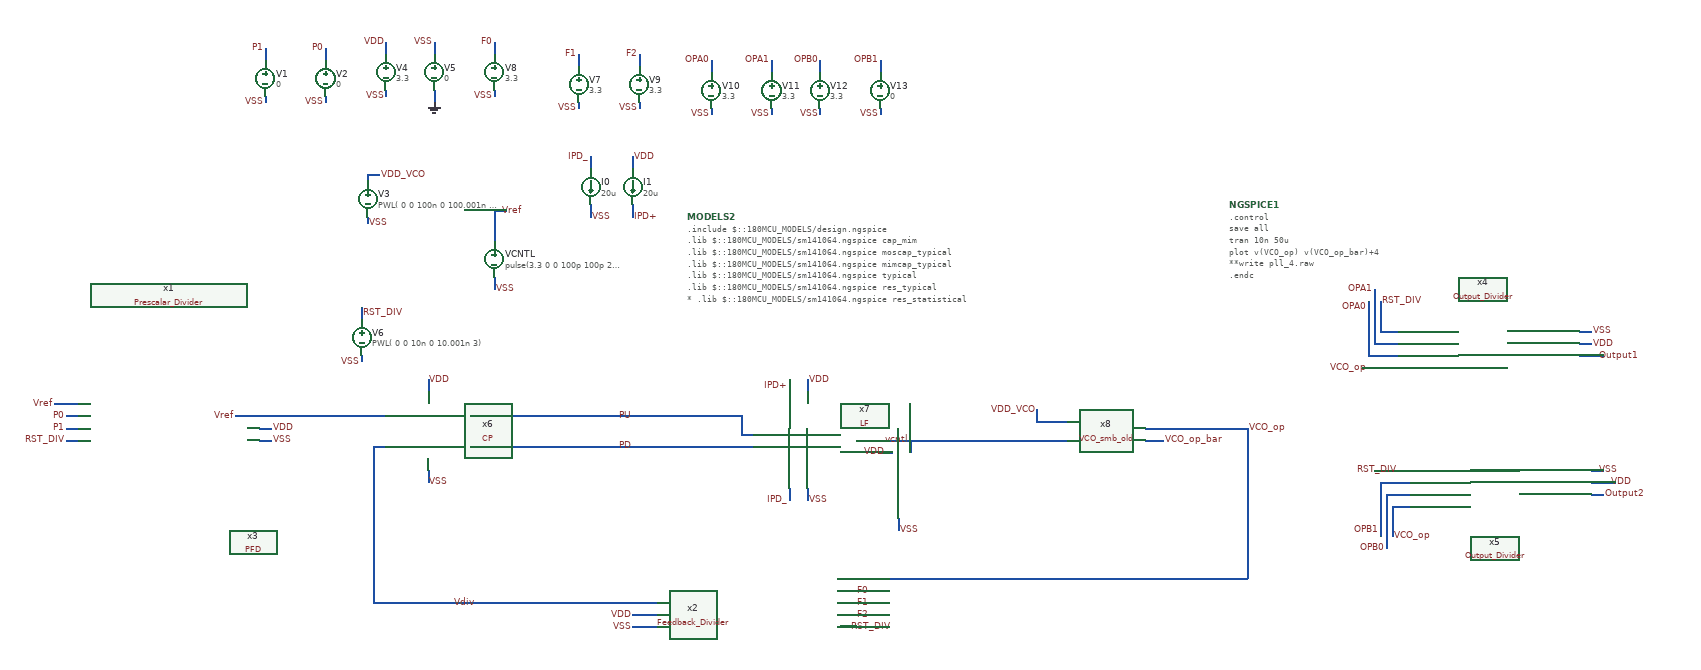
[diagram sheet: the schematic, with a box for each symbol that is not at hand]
v {xschem version=3.1.0 file_version=1.2
}
G {}
K {}
V {}
S {}
E {}
N 130 -460 150 -460 {
lab=P0}
N 130 -440 150 -440 {
lab=P1}
N 130 -420 150 -420 {
lab=RST_DIV}
N 450 -420 470 -420 {
lab=VSS}
N 450 -440 470 -440 {
lab=VDD}
N 460 -990 460 -980 {
lab=VSS}
N 460 -1070 460 -1050 {
lab=P1}
N 560 -990 560 -980 {
lab=VSS}
N 560 -1070 560 -1050 {
lab=P0}
N 730 -520 730 -500 {
lab=VDD}
N 730 -370 730 -350 {
lab=VSS}
N 640 -460 660 -460 {
lab=Vref}
N 640 -410 660 -410 {
lab=Vdiv}
N 800 -410 820 -410 {
lab=PD}
N 620 -460 640 -460 {
lab=Vref}
N 820 -460 910 -460 {
lab=PU}
N 820 -410 910 -410 {
lab=PD}
N 1100 -460 1250 -460 {
lab=PU}
N 1100 -410 1250 -410 {
lab=PD}
N 640 -410 640 -280 {
lab=Vdiv}
N 640 -180 640 -150 {
lab=Vdiv}
N 650 -150 940 -150 {
lab=Vdiv}
N 2030 -440 2090 -440 {
lab=VCO_op}
N 1970 -440 2030 -440 {
lab=VCO_op}
N 1920 -440 1970 -440 {
lab=VCO_op}
N 1740 -450 1780 -450 {
lab=VDD_VCO}
N 1920 -420 1950 -420 {
lab=VCO_op_bar}
N 640 -280 640 -180 {
lab=Vdiv}
N 640 -150 650 -150 {
lab=Vdiv}
N 800 -460 820 -460 {
lab=PU}
N 910 -460 1100 -460 {
lab=PU}
N 910 -410 1100 -410 {
lab=PD}
N 840 -690 840 -670 {
lab=VSS}
N 630 -790 630 -780 {
lab=VSS}
N 840 -800 860 -800 {
lab=Vref}
N 660 -1000 660 -990 {
lab=VSS}
N 660 -1080 660 -1060 {
lab=VDD}
N 740 -1080 740 -1060 {
lab=VSS}
N 740 -1000 740 -980 {
lab=GND}
N 1740 -470 1740 -450 {
lab=VDD_VCO}
N 940 -150 1110 -150 {
lab=Vdiv}
N 1070 -130 1110 -130 {
lab=VDD}
N 1070 -110 1110 -110 {
lab=VSS}
N 1410 -130 1440 -130 {
lab=F2}
N 1410 -110 1440 -110 {
lab=RST_DIV}
N 1440 -190 2090 -190 {
lab=VCO_op}
N 620 -560 620 -550 {
lab=VSS}
N 620 -640 620 -620 {
lab=RST_DIV}
N 2090 -440 2090 -420 {
lab=VCO_op}
N 1600 -420 1610 -420 {
lab=vcntl}
N 840 -800 840 -750 {
lab=Vref}
N 1780 -450 1790 -450 {
lab=VDD_VCO}
N 1610 -420 1770 -420 {
lab=vcntl}
N 1410 -190 1430 -190 {
lab=VCO_op}
N 1430 -190 1440 -190 {
lab=VCO_op}
N 2090 -420 2090 -190 {
lab=VCO_op}
N 1410 -170 1440 -170 {
lab=F0}
N 1410 -150 1440 -150 {
lab=F1}
N 630 -860 630 -850 {
lab=VDD_VCO}
N 630 -860 650 -860 {
lab=VDD_VCO}
N 980 -980 980 -970 {
lab=VSS}
N 980 -1060 980 -1040 {
lab=F1}
N 840 -1000 840 -990 {
lab=VSS}
N 840 -1080 840 -1060 {
lab=F0}
N 1080 -980 1080 -970 {
lab=VSS}
N 1080 -1060 1080 -1040 {
lab=F2}
N 2310 -600 2340 -600 {
lab=RST_DIV}
N 2310 -650 2310 -600 {
lab=RST_DIV}
N 2280 -540 2340 -540 {
lab=VCO_op}
N 2300 -580 2340 -580 {
lab=OPA1}
N 2300 -650 2300 -580 {
lab=OPA1}
N 2290 -560 2340 -560 {
lab=OPA0}
N 2290 -650 2290 -560 {
lab=OPA0}
N 2640 -600 2660 -600 {
lab=VSS}
N 2640 -580 2660 -580 {
lab=VDD}
N 2640 -560 2680 -560 {
lab=Output1}
N 2300 -670 2300 -650 {
lab=OPA1}
N 2330 -310 2360 -310 {
lab=VCO_op}
N 2330 -310 2330 -260 {
lab=VCO_op}
N 2300 -370 2360 -370 {
lab=RST_DIV}
N 2320 -330 2360 -330 {
lab=OPB0}
N 2320 -330 2320 -260 {
lab=OPB0}
N 2310 -350 2360 -350 {
lab=OPB1}
N 2310 -350 2310 -260 {
lab=OPB1}
N 2660 -370 2680 -370 {
lab=VSS}
N 2660 -330 2680 -330 {
lab=Output2}
N 2660 -350 2700 -350 {
lab=VDD}
N 2320 -260 2320 -240 {
lab=OPB0}
N 1200 -970 1200 -960 {
lab=VSS}
N 1200 -1050 1200 -1030 {
lab=OPA0}
N 1300 -970 1300 -960 {
lab=VSS}
N 1300 -1050 1300 -1030 {
lab=OPA1}
N 1380 -970 1380 -960 {
lab=VSS}
N 1380 -1050 1380 -1030 {
lab=OPB0}
N 1480 -970 1480 -960 {
lab=VSS}
N 1480 -1050 1480 -1030 {
lab=OPB1}
N 1360 -520 1360 -500 {
lab=VDD}
N 1360 -340 1360 -320 {
lab=VSS}
N 1250 -460 1250 -440 {
lab=PU}
N 1250 -440 1250 -430 {
lab=PU}
N 1250 -430 1270 -430 {
lab=PU}
N 1250 -410 1270 -410 {
lab=PD}
N 1510 -290 1510 -270 {
lab=VSS}
N 1330 -520 1330 -500 {
lab=IPD+}
N 1330 -340 1330 -320 {
lab=IPD_}
N 1440 -420 1600 -420 {
lab=vcntl}
N 1000 -810 1000 -790 {
lab=VSS}
N 1070 -810 1070 -790 {
lab=IPD+}
N 1000 -890 1000 -870 {
lab=IPD_}
N 1070 -890 1070 -870 {
lab=VDD}
N 540 -460 570 -460 {
lab=Vref}
N 1530 -420 1530 -400 {
lab=vcntl}
N 1480 -400 1500 -400 {
lab=VDD}
N 1770 -420 1790 -420 {
lab=vcntl}
N 570 -460 620 -460 {
lab=Vref}
N 110 -480 140 -480 {
lab=Vref}
N 450 -460 520 -460 {
lab=Vref}
N 520 -460 540 -460 {
lab=Vref}
N 140 -480 150 -480 {
lab=Vref}
N 410 -460 440 -460 {
lab=Vref}
N 440 -460 450 -460 {
lab=Vref}
C {devices/lab_pin.sym} 130 -440 0 0 {name=p139 sig_type=std_logic lab=P1}
C {devices/lab_pin.sym} 130 -460 0 0 {name=p140 sig_type=std_logic lab=P0}
C {devices/lab_pin.sym} 110 -480 0 0 {name=p141 sig_type=std_logic lab=Vref
}
C {devices/lab_pin.sym} 470 -420 2 0 {name=p142 sig_type=std_logic lab=VSS}
C {devices/lab_pin.sym} 470 -440 2 0 {name=p143 sig_type=std_logic lab=VDD}
C {devices/lab_pin.sym} 130 -420 0 0 {name=p144 sig_type=std_logic lab=RST_DIV}
C {devices/vsource.sym} 460 -1020 0 0 {name=V1 value=0}
C {devices/lab_wire.sym} 460 -980 0 0 {name=p1 sig_type=std_logic lab=VSS
}
C {devices/lab_wire.sym} 460 -1070 0 0 {name=p2 sig_type=std_logic lab=P1}
C {devices/vsource.sym} 560 -1020 0 0 {name=V2 value=0}
C {devices/lab_wire.sym} 560 -980 0 0 {name=p3 sig_type=std_logic lab=VSS
}
C {devices/lab_wire.sym} 560 -1070 0 0 {name=p4 sig_type=std_logic lab=P0}
C {PFD.sym} 440 -250 0 0 {name=x3}
C {devices/lab_pin.sym} 730 -520 2 0 {name=p9 sig_type=std_logic lab=VDD}
C {devices/lab_wire.sym} 730 -350 2 0 {name=p10 sig_type=std_logic lab=VSS}
C {devices/lab_pin.sym} 810 -150 3 0 {name=p28 sig_type=std_logic lab=Vdiv
}
C {devices/lab_pin.sym} 2090 -440 2 0 {name=p36 sig_type=std_logic lab=VCO_op
}
C {devices/vsource.sym} 840 -720 0 0 {name=VCNTL value="pulse(3.3 0 0 100p 100p 250n 500n)"}
C {devices/vsource.sym} 630 -820 0 0 {name=V3 value=" PWL( 0 0 100n 0 100.001n 3.3)"}
C {devices/code_shown.sym} 2060 -810 0 1 {name=NGSPICE1 only_toplevel=true
value="
.control
save all
tran 10n 50u 
plot v(VCO_op) v(VCO_op_bar)+4
**write pll_4.raw
.endc
"}
C {devices/vsource.sym} 660 -1030 0 0 {name=V4 value=3.3}
C {devices/vsource.sym} 740 -1030 0 0 {name=V5 value=0}
C {devices/lab_wire.sym} 740 -1080 0 0 {name=p7 sig_type=std_logic lab=VSS}
C {devices/lab_wire.sym} 660 -990 0 0 {name=p8 sig_type=std_logic lab=VSS
}
C {devices/lab_wire.sym} 660 -1080 0 0 {name=p11 sig_type=std_logic lab=VDD}
C {devices/gnd.sym} 740 -980 0 0 {name=l3 lab=GND}
C {devices/lab_pin.sym} 1740 -470 0 0 {name=p12 sig_type=std_logic lab=VDD_VCO}
C {devices/lab_pin.sym} 1950 -420 2 0 {name=p13 sig_type=std_logic lab=VCO_op_bar
}
C {devices/lab_pin.sym} 1070 -130 0 0 {name=p14 sig_type=std_logic lab=VDD}
C {devices/lab_wire.sym} 1070 -110 3 0 {name=p15 sig_type=std_logic lab=VSS}
C {devices/lab_pin.sym} 650 -860 2 0 {name=p16 sig_type=std_logic lab=VDD_VCO}
C {devices/lab_pin.sym} 850 -800 2 0 {name=p17 sig_type=std_logic lab=Vref
}
C {devices/lab_wire.sym} 620 -550 0 0 {name=p18 sig_type=std_logic lab=VSS
}
C {devices/vsource.sym} 620 -590 0 0 {name=V6 value=" PWL( 0 0 10n 0 10.001n 3)"}
C {devices/lab_pin.sym} 1530 -420 1 0 {name=p19 sig_type=std_logic lab=vcntl
}
C {devices/lab_pin.sym} 1070 -460 1 0 {name=p20 sig_type=std_logic lab=PU}
C {devices/lab_pin.sym} 1070 -410 1 0 {name=p21 sig_type=std_logic lab=PD}
C {Feedback_Divider.sym} 1260 -150 2 0 {name=x2}
C {devices/lab_pin.sym} 1440 -170 2 0 {name=p22 sig_type=std_logic lab=F0}
C {devices/lab_pin.sym} 1440 -150 2 0 {name=p23 sig_type=std_logic lab=F1}
C {devices/lab_pin.sym} 1440 -130 2 0 {name=p24 sig_type=std_logic lab=F2}
C {devices/vsource.sym} 980 -1010 0 0 {name=V7 value=3.3}
C {devices/lab_wire.sym} 980 -970 0 0 {name=p26 sig_type=std_logic lab=VSS
}
C {devices/lab_wire.sym} 980 -1060 0 0 {name=p27 sig_type=std_logic lab=F1}
C {devices/vsource.sym} 840 -1030 0 0 {name=V8 value=3.3}
C {devices/lab_wire.sym} 840 -990 0 0 {name=p25 sig_type=std_logic lab=VSS
}
C {devices/lab_wire.sym} 840 -1080 0 0 {name=p29 sig_type=std_logic lab=F0}
C {devices/vsource.sym} 1080 -1010 0 0 {name=V9 value=3.3}
C {devices/lab_wire.sym} 1080 -970 0 0 {name=p30 sig_type=std_logic lab=VSS
}
C {devices/lab_wire.sym} 1080 -1060 0 0 {name=p31 sig_type=std_logic lab=F2}
C {devices/lab_pin.sym} 2660 -580 2 0 {name=p32 sig_type=std_logic lab=VDD}
C {devices/lab_pin.sym} 2660 -600 2 0 {name=p33 sig_type=std_logic lab=VSS}
C {devices/lab_wire.sym} 2290 -640 0 0 {name=p82 sig_type=std_logic lab=OPA0}
C {devices/lab_wire.sym} 2300 -670 0 0 {name=p83 sig_type=std_logic lab=OPA1}
C {devices/lab_pin.sym} 2310 -650 2 0 {name=p34 sig_type=std_logic lab=RST_DIV}
C {devices/lab_pin.sym} 2670 -560 2 0 {name=p84 sig_type=std_logic lab=Output1}
C {devices/lab_pin.sym} 2690 -350 0 1 {name=p85 sig_type=std_logic lab=VDD}
C {devices/lab_pin.sym} 2670 -370 0 1 {name=p86 sig_type=std_logic lab=VSS}
C {devices/lab_wire.sym} 2310 -270 2 1 {name=p87 sig_type=std_logic lab=OPB1}
C {devices/lab_wire.sym} 2320 -240 2 1 {name=p88 sig_type=std_logic lab=OPB0}
C {devices/lab_pin.sym} 2680 -330 0 1 {name=p90 sig_type=std_logic lab=Output2}
C {Output_Divider.sym} 2510 -340 0 0 {name=x5}
C {devices/lab_pin.sym} 2340 -370 1 0 {name=p35 sig_type=std_logic lab=RST_DIV}
C {devices/lab_pin.sym} 2330 -260 2 0 {name=p37 sig_type=std_logic lab=VCO_op
}
C {devices/lab_pin.sym} 2290 -540 2 1 {name=p40 sig_type=std_logic lab=VCO_op
}
C {devices/vsource.sym} 1200 -1000 0 0 {name=V10 value=3.3}
C {devices/lab_wire.sym} 1200 -960 0 0 {name=p41 sig_type=std_logic lab=VSS
}
C {devices/lab_wire.sym} 1200 -1050 0 0 {name=p42 sig_type=std_logic lab=OPA0}
C {devices/vsource.sym} 1300 -1000 0 0 {name=V11 value=3.3}
C {devices/lab_wire.sym} 1300 -960 0 0 {name=p43 sig_type=std_logic lab=VSS
}
C {devices/lab_wire.sym} 1300 -1050 0 0 {name=p44 sig_type=std_logic lab=OPA1}
C {devices/vsource.sym} 1380 -1000 0 0 {name=V12 value=3.3}
C {devices/lab_wire.sym} 1380 -960 0 0 {name=p45 sig_type=std_logic lab=VSS
}
C {devices/lab_wire.sym} 1380 -1050 0 0 {name=p46 sig_type=std_logic lab=OPB0
}
C {devices/vsource.sym} 1480 -1000 0 0 {name=V13 value=0}
C {devices/lab_wire.sym} 1480 -960 0 0 {name=p47 sig_type=std_logic lab=VSS
}
C {devices/lab_wire.sym} 1480 -1050 0 0 {name=p48 sig_type=std_logic lab=OPB1}
C {devices/lab_pin.sym} 620 -630 2 0 {name=p38 sig_type=std_logic lab=RST_DIV}
C {devices/lab_pin.sym} 1430 -110 2 0 {name=p39 sig_type=std_logic lab=RST_DIV}
C {devices/lab_wire.sym} 1360 -320 2 0 {name=p49 sig_type=std_logic lab=VSS}
C {devices/lab_pin.sym} 1360 -520 2 0 {name=p50 sig_type=std_logic lab=VDD}
C {CP.sym} 780 -220 0 0 {name=x6}
C {LF.sym} 1370 -240 0 0 {name=x7}
C {devices/lab_wire.sym} 1510 -270 2 0 {name=p51 sig_type=std_logic lab=VSS}
C {devices/lab_wire.sym} 1330 -510 0 0 {name=p52 sig_type=std_logic lab=IPD+}
C {devices/lab_wire.sym} 1330 -320 0 0 {name=p53 sig_type=std_logic lab=IPD_}
C {devices/isource.sym} 1000 -840 0 0 {name=I0 value=20u}
C {devices/isource.sym} 1070 -840 0 0 {name=I1 value=20u}
C {devices/lab_wire.sym} 1000 -890 0 0 {name=p54 sig_type=std_logic lab=IPD_}
C {devices/lab_wire.sym} 1070 -790 2 0 {name=p55 sig_type=std_logic lab=IPD+}
C {devices/lab_wire.sym} 1000 -790 2 0 {name=p56 sig_type=std_logic lab=VSS}
C {devices/lab_wire.sym} 1070 -890 2 0 {name=p57 sig_type=std_logic lab=VDD}
C {Output_Divider.sym} 2490 -570 0 0 {name=x4}
C {devices/code_shown.sym} 1160 -790 0 0 {name=MODELS2 only_toplevel=true
format="tcleval( @value )"
value="
.include $::180MCU_MODELS/design.ngspice
.lib $::180MCU_MODELS/sm141064.ngspice cap_mim
.lib $::180MCU_MODELS/sm141064.ngspice moscap_typical
.lib $::180MCU_MODELS/sm141064.ngspice mimcap_typical
.lib $::180MCU_MODELS/sm141064.ngspice typical
.lib $::180MCU_MODELS/sm141064.ngspice res_typical
* .lib $::180MCU_MODELS/sm141064.ngspice res_statistical
"}
C {devices/lab_pin.sym} 1490 -400 0 0 {name=p59 sig_type=std_logic lab=VDD}
C {VCO_smb_old.sym} 1940 -430 0 0 {name=x8}
C {Prescalar_Divider.sym} 300 -450 2 1 {name=x1}
C {devices/lab_wire.sym} 630 -780 2 0 {name=p5 sig_type=std_logic lab=VSS
}
C {devices/lab_wire.sym} 840 -670 2 0 {name=p6 sig_type=std_logic lab=VSS
}
C {devices/lab_pin.sym} 410 -460 0 0 {name=p58 sig_type=std_logic lab=Vref
}
